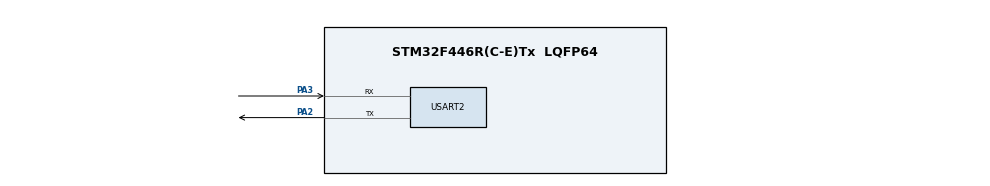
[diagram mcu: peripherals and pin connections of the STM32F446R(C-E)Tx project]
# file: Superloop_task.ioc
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Mcu.Family=STM32F4
Mcu.Name=STM32F446R(C-E)Tx
Mcu.Package=LQFP64
NVIC.PriorityGroup=NVIC_PRIORITYGROUP_4
NVIC.RCC_IRQn=true\:0\:0\:false\:false\:true\:true\:false\:true
NVIC.USART2_IRQn=true\:0\:0\:false\:false\:true\:true\:true\:true
PA2.Mode=Asynchronous
PA2.Signal=USART2_TX
PA3.Mode=Asynchronous
PA3.Signal=USART2_RX
PC14-OSC32_IN.Mode=LSE-External-Oscillator
PC14-OSC32_IN.Signal=RCC_OSC32_IN
PC15-OSC32_OUT.Mode=LSE-External-Oscillator
PC15-OSC32_OUT.Signal=RCC_OSC32_OUT
PH0-OSC_IN.Mode=HSE-External-Oscillator
PH0-OSC_IN.Signal=RCC_OSC_IN
PH1-OSC_OUT.Mode=HSE-External-Oscillator
PH1-OSC_OUT.Signal=RCC_OSC_OUT
ProjectManager.HeapSize=0x200
ProjectManager.StackSize=0x400
ProjectManager.TargetToolchain=STM32CubeIDE
RCC.CortexFreq_Value=16000000
RCC.USBFreq_Value=96000000
RCC.VCOOutputFreq_Value=192000000
USART2.VirtualMode=VM_ASYNC
board=custom

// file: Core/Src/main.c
/* USER CODE BEGIN Header */
/**
  ******************************************************************************
  * @file           : main.c
  * @brief          : Main program body
  ******************************************************************************
  * @attention
  *
  * Copyright (c) 2025 STMicroelectronics.
  * All rights reserved.
  *
  * This software is licensed under terms that can be found in the LICENSE file
  * in the root directory of this software component.
  * If no LICENSE file comes with this software, it is provided AS-IS.
  *
  ******************************************************************************
  */
/* USER CODE END Header */
#include "main.h"
uint8_t flag_button_pressed = 0;
uint8_t flag_sensor_ready = 0;
uint8_t flag_uart_received = 0;

UART_HandleTypeDef huart2;

void SystemClock_Config(void);
static void MX_GPIO_Init(void);
static void MX_USART2_UART_Init(void);

uint8_t rx_data;
int main(void)
{

  /* MCU Configuration--------------------------------------------------------*/

  /* Reset of all peripherals, Initializes the Flash interface and the Systick. */
  HAL_Init();

  /* Configure the system clock */
  SystemClock_Config();

  /* Initialize all configured peripherals */
  MX_GPIO_Init();
  MX_USART2_UART_Init();
  HAL_UART_Receive_IT(&huart2, &rx_data, 1);

  /* Infinite loop */
  while (1)
  {
	  if (flag_button_pressed) {
	        HAL_GPIO_TogglePin(GPIOA, GPIO_PIN_5);  // Toggle LED
	        flag_button_pressed = 0;
	      }

	      if (flag_sensor_ready) {
	        // Simulate reading sensor
	        HAL_UART_Transmit(&huart2, (uint8_t*)"Sensor Ready\r\n", 14, HAL_MAX_DELAY);
	        flag_sensor_ready = 0;
	      }

	      if (flag_uart_received) {
	          HAL_UART_Transmit(&huart2, (uint8_t*)"You typed: ", 11, HAL_MAX_DELAY);
	          HAL_UART_Transmit(&huart2, &rx_data, 1, HAL_MAX_DELAY);
	          HAL_UART_Transmit(&huart2, (uint8_t*)"\r\n", 2, HAL_MAX_DELAY);
	          flag_uart_received = 0;
	      }

	      // Simulate setting the sensor flag every few cycles (for demo only)
	      HAL_Delay(1000);
	      flag_sensor_ready = 1;
  }
}
void HAL_GPIO_EXTI_Callback(uint16_t GPIO_Pin)
{
  if (GPIO_Pin == GPIO_PIN_13) {
    flag_button_pressed = 1;
  }
}
// UART receive complete callback
void HAL_UART_RxCpltCallback(UART_HandleTypeDef *huart) {
    if (huart->Instance == USART2) {
        flag_uart_received = 1;

        // VERY IMPORTANT: re-enable interrupt reception
        HAL_UART_Receive_IT(&huart2, &rx_data, 1);
    }
}

void SystemClock_Config(void)
{
  RCC_OscInitTypeDef RCC_OscInitStruct = {0};
  RCC_ClkInitTypeDef RCC_ClkInitStruct = {0};

  /** Configure the main internal regulator output voltage
  */
  __HAL_RCC_PWR_CLK_ENABLE();
  __HAL_PWR_VOLTAGESCALING_CONFIG(PWR_REGULATOR_VOLTAGE_SCALE3);

  /** Initializes the RCC Oscillators according to the specified parameters
  * in the RCC_OscInitTypeDef structure.
  */
  RCC_OscInitStruct.OscillatorType = RCC_OSCILLATORTYPE_HSI;
  RCC_OscInitStruct.HSIState = RCC_HSI_ON;
  RCC_OscInitStruct.HSICalibrationValue = RCC_HSICALIBRATION_DEFAULT;
  RCC_OscInitStruct.PLL.PLLState = RCC_PLL_NONE;
  if (HAL_RCC_OscConfig(&RCC_OscInitStruct) != HAL_OK)
  {
    Error_Handler();
  }

  /** Initializes the CPU, AHB and APB buses clocks
  */
  RCC_ClkInitStruct.ClockType = RCC_CLOCKTYPE_HCLK|RCC_CLOCKTYPE_SYSCLK
                              |RCC_CLOCKTYPE_PCLK1|RCC_CLOCKTYPE_PCLK2;
  RCC_ClkInitStruct.SYSCLKSource = RCC_SYSCLKSOURCE_HSI;
  RCC_ClkInitStruct.AHBCLKDivider = RCC_SYSCLK_DIV1;
  RCC_ClkInitStruct.APB1CLKDivider = RCC_HCLK_DIV1;
  RCC_ClkInitStruct.APB2CLKDivider = RCC_HCLK_DIV1;

  if (HAL_RCC_ClockConfig(&RCC_ClkInitStruct, FLASH_LATENCY_0) != HAL_OK)
  {
    Error_Handler();
  }
}

static void MX_USART2_UART_Init(void)
{

  huart2.Instance = USART2;
  huart2.Init.BaudRate = 115200;
  huart2.Init.WordLength = UART_WORDLENGTH_8B;
  huart2.Init.StopBits = UART_STOPBITS_1;
  huart2.Init.Parity = UART_PARITY_NONE;
  huart2.Init.Mode = UART_MODE_TX_RX;
  huart2.Init.HwFlowCtl = UART_HWCONTROL_NONE;
  huart2.Init.OverSampling = UART_OVERSAMPLING_16;
  if (HAL_UART_Init(&huart2) != HAL_OK)
  {
    Error_Handler();
  }

}

static void MX_GPIO_Init(void)
{

  /* GPIO Ports Clock Enable */
	GPIO_InitTypeDef GPIO_InitStruct = {0};

	  /* GPIO Ports Clock Enable */
	  __HAL_RCC_GPIOC_CLK_ENABLE();   // For PC13 (Button)
	  __HAL_RCC_GPIOA_CLK_ENABLE();   // For PA5 (LED)

	  /* Configure GPIO pin : PC13 (Button Input with External Interrupt) */
	  GPIO_InitStruct.Pin = GPIO_PIN_13;
	  GPIO_InitStruct.Mode = GPIO_MODE_IT_FALLING;
	  GPIO_InitStruct.Pull = GPIO_NOPULL;  // Change to GPIO_PULLUP if needed
	  HAL_GPIO_Init(GPIOC, &GPIO_InitStruct);

	  /* Configure GPIO pin : PA5 (LED Output) */
	  GPIO_InitStruct.Pin = GPIO_PIN_5;
	  GPIO_InitStruct.Mode = GPIO_MODE_OUTPUT_PP;
	  GPIO_InitStruct.Pull = GPIO_NOPULL;
	  GPIO_InitStruct.Speed = GPIO_SPEED_FREQ_LOW;
	  HAL_GPIO_Init(GPIOA, &GPIO_InitStruct);

	  /* EXTI interrupt init */
	  HAL_NVIC_SetPriority(EXTI15_10_IRQn, 0, 0);
	  HAL_NVIC_EnableIRQ(EXTI15_10_IRQn);
}

void Error_Handler(void)
{
  __disable_irq();
  while (1)
  {
  }
}
